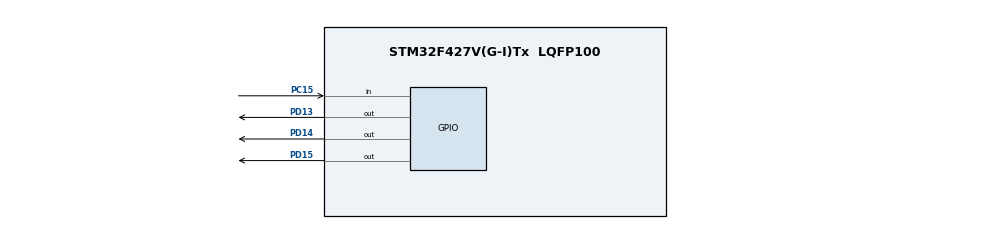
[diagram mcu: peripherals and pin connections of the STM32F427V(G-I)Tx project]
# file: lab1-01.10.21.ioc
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Mcu.Family=STM32F4
Mcu.Name=STM32F427V(G-I)Tx
Mcu.Package=LQFP100
NVIC.PriorityGroup=NVIC_PRIORITYGROUP_4
PA13.Mode=JTAG_5_pins
PA13.Signal=SYS_JTMS-SWDIO
PA14.Mode=JTAG_5_pins
PA14.Signal=SYS_JTCK-SWCLK
PA15.Mode=JTAG_5_pins
PA15.Signal=SYS_JTDI
PB3.Mode=JTAG_5_pins
PB3.Signal=SYS_JTDO-SWO
PB4.Mode=JTAG_5_pins
PB4.Signal=SYS_JTRST
PC15/OSC32_OUT.Signal=GPIO_Input
PD13.Signal=GPIO_Output
PD14.Signal=GPIO_Output
PD15.Signal=GPIO_Output
ProjectManager.HeapSize=0x200
ProjectManager.StackSize=0x400
ProjectManager.TargetToolchain=STM32CubeIDE
RCC.AHBFreq_Value=16000000
RCC.APB1Freq_Value=16000000
RCC.APB2Freq_Value=16000000
RCC.CortexFreq_Value=16000000
RCC.HSE_VALUE=25000000
RCC.HSI_VALUE=16000000
RCC.LSE_VALUE=32768
RCC.SYSCLKFreq_VALUE=16000000
RCC.VCOOutputFreq_Value=192000000
board=custom

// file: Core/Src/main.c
/* USER CODE BEGIN Header */
/**
  ******************************************************************************
  * @file           : main.c
  * @brief          : Main program body
  ******************************************************************************
  * @attention
  *
  * <h2><center>&copy; Copyright (c) 2021 STMicroelectronics.
  * All rights reserved.</center></h2>
  *
  * This software component is licensed by ST under BSD 3-Clause license,
  * the "License"; You may not use this file except in compliance with the
  * License. You may obtain a copy of the License at:
  *                        opensource.org/licenses/BSD-3-Clause
  *
  ******************************************************************************
  */
/* USER CODE END Header */
#include "main.h"
#include "gpio.h"
#include <stdbool.h>
#include "LEDMode.c"
#include "utils.h"
#define MODES_AMOUNT 4

void SystemClock_Config(void);

/* USER CODE BEGIN 0 */

struct LEDMode MODES[] = {
		  { 6, { -1,GPIO_PIN_13,-1,GPIO_PIN_13,-1,GPIO_PIN_13 }, 1000,0 },
		  { 6, { -1,GPIO_PIN_14,-1,GPIO_PIN_14,-1,GPIO_PIN_14 }, 200,0 },
		  { 6, { -1,GPIO_PIN_15,-1,GPIO_PIN_15,-1,GPIO_PIN_15 }, 1000,0 },
		  { 6, { -1,GPIO_PIN_15,-1,GPIO_PIN_13,-1,GPIO_PIN_14 }, 500,0 }
};

bool activate_LEDMode(struct LEDMode* current_mode) {
	bool clicked_while_animation = false;
	uint32_t led = current_mode->code[current_mode->current_code_index];
	if (led == -1) {
		int start_time = HAL_GetTick();
		while (HAL_GetTick() < start_time + current_mode->delay_time)
			if (is_btn_pressed() == true) clicked_while_animation = true;
	} else HAL_GPIO_TogglePin(GPIOD, led);
	current_mode->current_code_index++;
	return clicked_while_animation;
}

/* USER CODE END 0 */

int main(void) {

  /* USER CODE END 1 */

  /* MCU Configuration--------------------------------------------------------*/

  /* Reset of all peripherals, Initializes the Flash interface and the Systick. */
  HAL_Init();

  /* Configure the system clock */
  SystemClock_Config();

  /* Initialize all configured peripherals */
  MX_GPIO_Init();

  /* Infinite loop */
  /* USER CODE BEGIN WHILE */

  int cur_mode_index = 0;
  bool flag;
  while (1) {
	  flag = activate_LEDMode(&MODES[cur_mode_index ]);
	  if (MODES[cur_mode_index ].current_code_index > MODES[cur_mode_index ].lenght) MODES[cur_mode_index ].current_code_index = 0;
	  if (flag || is_btn_pressed()) {
		  reset_LEDs();
		  cur_mode_index += 1;
		  if (cur_mode_index >= MODES_AMOUNT) cur_mode_index = 0;
	  }
  }

    /* USER CODE END WHILE */

  }

void SystemClock_Config(void)
{
  RCC_OscInitTypeDef RCC_OscInitStruct = {0};
  RCC_ClkInitTypeDef RCC_ClkInitStruct = {0};

  /** Configure the main internal regulator output voltage
  */
  __HAL_RCC_PWR_CLK_ENABLE();
  __HAL_PWR_VOLTAGESCALING_CONFIG(PWR_REGULATOR_VOLTAGE_SCALE1);
  /** Initializes the RCC Oscillators according to the specified parameters
  * in the RCC_OscInitTypeDef structure.
  */
  RCC_OscInitStruct.OscillatorType = RCC_OSCILLATORTYPE_HSE;
  RCC_OscInitStruct.HSEState = RCC_HSE_ON;
  RCC_OscInitStruct.PLL.PLLState = RCC_PLL_ON;
  RCC_OscInitStruct.PLL.PLLSource = RCC_PLLSOURCE_HSE;
  RCC_OscInitStruct.PLL.PLLM = 15;
  RCC_OscInitStruct.PLL.PLLN = 216;
  RCC_OscInitStruct.PLL.PLLP = RCC_PLLP_DIV2;
  RCC_OscInitStruct.PLL.PLLQ = 4;
  if (HAL_RCC_OscConfig(&RCC_OscInitStruct) != HAL_OK)
  {
    Error_Handler();
  }
  /** Activate the Over-Drive mode
  */
  if (HAL_PWREx_EnableOverDrive() != HAL_OK)
  {
    Error_Handler();
  }
  /** Initializes the CPU, AHB and APB buses clocks
  */
  RCC_ClkInitStruct.ClockType = RCC_CLOCKTYPE_HCLK|RCC_CLOCKTYPE_SYSCLK
                              |RCC_CLOCKTYPE_PCLK1|RCC_CLOCKTYPE_PCLK2;
  RCC_ClkInitStruct.SYSCLKSource = RCC_SYSCLKSOURCE_PLLCLK;
  RCC_ClkInitStruct.AHBCLKDivider = RCC_SYSCLK_DIV1;
  RCC_ClkInitStruct.APB1CLKDivider = RCC_HCLK_DIV4;
  RCC_ClkInitStruct.APB2CLKDivider = RCC_HCLK_DIV2;

  if (HAL_RCC_ClockConfig(&RCC_ClkInitStruct, FLASH_LATENCY_5) != HAL_OK)
  {
    Error_Handler();
  }
}

void Error_Handler(void)
{
  __disable_irq();
  while (1)
  {
  }
}

/************************ (C) COPYRIGHT STMicroelectronics *****END OF FILE****/
